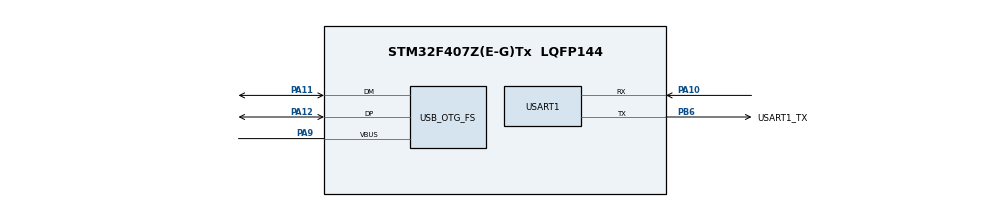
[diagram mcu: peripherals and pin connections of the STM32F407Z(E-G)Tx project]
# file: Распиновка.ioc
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Mcu.Family=STM32F4
Mcu.Name=STM32F407Z(E-G)Tx
Mcu.Package=LQFP144
NVIC.PriorityGroup=NVIC_PRIORITYGROUP_4
NVIC.USART1_IRQn=true\:0\:0\:false\:false\:true\:true\:true\:true
PA10.Mode=Asynchronous
PA10.Signal=USART1_RX
PA11.Mode=Host_Only
PA11.Signal=USB_OTG_FS_DM
PA12.Mode=Host_Only
PA12.Signal=USB_OTG_FS_DP
PA9.Mode=Activate_VBUS
PA9.Signal=USB_OTG_FS_VBUS
PB6.GPIO_Label=USART1_TX
PB6.Mode=Asynchronous
PB6.Signal=USART1_TX
ProjectManager.HeapSize=0x200
ProjectManager.StackSize=0x400
ProjectManager.TargetToolchain=EWARM V8.50
RCC.48MHZClocksFreq_Value=25000000
RCC.AHBFreq_Value=50000000
RCC.APB1CLKDivider=RCC_HCLK_DIV2
RCC.APB1Freq_Value=25000000
RCC.APB1TimFreq_Value=50000000
RCC.APB2Freq_Value=50000000
RCC.APB2TimFreq_Value=50000000
RCC.CortexFreq_Value=50000000
RCC.HCLKFreq_Value=50000000
RCC.HSE_VALUE=25000000
RCC.HSI_VALUE=16000000
RCC.LSE_VALUE=32768
RCC.PLLM=8
RCC.PLLN=50
RCC.PLLSource=RCC_PLLSOURCE_HSI
RCC.SYSCLKFreq_VALUE=50000000
RCC.SYSCLKSource=RCC_SYSCLKSOURCE_PLLCLK
RCC.VCOOutputFreq_Value=100000000
USART1.VirtualMode=VM_ASYNC
USB_OTG_FS.VirtualMode=Host_Only
USB_OTG_FS.phy_itface=HCD_PHY_EMBEDDED
board=custom

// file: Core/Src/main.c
/* USER CODE BEGIN Header */
/**
  ******************************************************************************
  * @file           : main.c
  * @brief          : Main program body
  ******************************************************************************
  * @attention
  *
  * Copyright (c) 2026 STMicroelectronics.
  * All rights reserved.
  *
  * This software is licensed under terms that can be found in the LICENSE file
  * in the root directory of this software component.
  * If no LICENSE file comes with this software, it is provided AS-IS.
  *
  ******************************************************************************
  */
/* USER CODE END Header */
#include "main.h"

UART_HandleTypeDef huart1;

HCD_HandleTypeDef hhcd_USB_OTG_FS;

void SystemClock_Config(void);
static void MX_GPIO_Init(void);
static void MX_USART1_UART_Init(void);
static void MX_USB_OTG_FS_HCD_Init(void);

int main(void)
{

  /* MCU Configuration--------------------------------------------------------*/

  /* Reset of all peripherals, Initializes the Flash interface and the Systick. */
  HAL_Init();

  /* Configure the system clock */
  SystemClock_Config();

  /* Initialize all configured peripherals */
  MX_GPIO_Init();
  MX_USART1_UART_Init();
  MX_USB_OTG_FS_HCD_Init();

  /* Infinite loop */
  while (1)
  {

  }
}

void SystemClock_Config(void)
{
  RCC_OscInitTypeDef RCC_OscInitStruct = {0};
  RCC_ClkInitTypeDef RCC_ClkInitStruct = {0};

  /** Configure the main internal regulator output voltage
  */
  __HAL_RCC_PWR_CLK_ENABLE();
  __HAL_PWR_VOLTAGESCALING_CONFIG(PWR_REGULATOR_VOLTAGE_SCALE1);

  /** Initializes the RCC Oscillators according to the specified parameters
  * in the RCC_OscInitTypeDef structure.
  */
  RCC_OscInitStruct.OscillatorType = RCC_OSCILLATORTYPE_HSE;
  RCC_OscInitStruct.HSEState = RCC_HSE_ON;
  RCC_OscInitStruct.PLL.PLLState = RCC_PLL_ON;
  RCC_OscInitStruct.PLL.PLLSource = RCC_PLLSOURCE_HSE;
  RCC_OscInitStruct.PLL.PLLM = 15;
  RCC_OscInitStruct.PLL.PLLN = 144;
  RCC_OscInitStruct.PLL.PLLP = RCC_PLLP_DIV2;
  RCC_OscInitStruct.PLL.PLLQ = 5;
  if (HAL_RCC_OscConfig(&RCC_OscInitStruct) != HAL_OK)
  {
    Error_Handler();
  }

  /** Initializes the CPU, AHB and APB buses clocks
  */
  RCC_ClkInitStruct.ClockType = RCC_CLOCKTYPE_HCLK|RCC_CLOCKTYPE_SYSCLK
                              |RCC_CLOCKTYPE_PCLK1|RCC_CLOCKTYPE_PCLK2;
  RCC_ClkInitStruct.SYSCLKSource = RCC_SYSCLKSOURCE_PLLCLK;
  RCC_ClkInitStruct.AHBCLKDivider = RCC_SYSCLK_DIV1;
  RCC_ClkInitStruct.APB1CLKDivider = RCC_HCLK_DIV4;
  RCC_ClkInitStruct.APB2CLKDivider = RCC_HCLK_DIV2;

  if (HAL_RCC_ClockConfig(&RCC_ClkInitStruct, FLASH_LATENCY_3) != HAL_OK)
  {
    Error_Handler();
  }
}

static void MX_USART1_UART_Init(void)
{

  huart1.Instance = USART1;
  huart1.Init.BaudRate = 115200;
  huart1.Init.WordLength = UART_WORDLENGTH_8B;
  huart1.Init.StopBits = UART_STOPBITS_1;
  huart1.Init.Parity = UART_PARITY_NONE;
  huart1.Init.Mode = UART_MODE_TX_RX;
  huart1.Init.HwFlowCtl = UART_HWCONTROL_NONE;
  huart1.Init.OverSampling = UART_OVERSAMPLING_16;
  if (HAL_UART_Init(&huart1) != HAL_OK)
  {
    Error_Handler();
  }

}

static void MX_USB_OTG_FS_HCD_Init(void)
{

  hhcd_USB_OTG_FS.Instance = USB_OTG_FS;
  hhcd_USB_OTG_FS.Init.Host_channels = 8;
  hhcd_USB_OTG_FS.Init.speed = HCD_SPEED_FULL;
  hhcd_USB_OTG_FS.Init.dma_enable = DISABLE;
  hhcd_USB_OTG_FS.Init.phy_itface = HCD_PHY_EMBEDDED;
  hhcd_USB_OTG_FS.Init.Sof_enable = DISABLE;
  if (HAL_HCD_Init(&hhcd_USB_OTG_FS) != HAL_OK)
  {
    Error_Handler();
  }

}

static void MX_GPIO_Init(void)
{

  /* GPIO Ports Clock Enable */
  __HAL_RCC_GPIOH_CLK_ENABLE();
  __HAL_RCC_GPIOA_CLK_ENABLE();
  __HAL_RCC_GPIOB_CLK_ENABLE();

}

void Error_Handler(void)
{
  __disable_irq();
  while (1)
  {
  }
}
